VERSION 5.7 ;
BUSBITCHARS "[]" ;
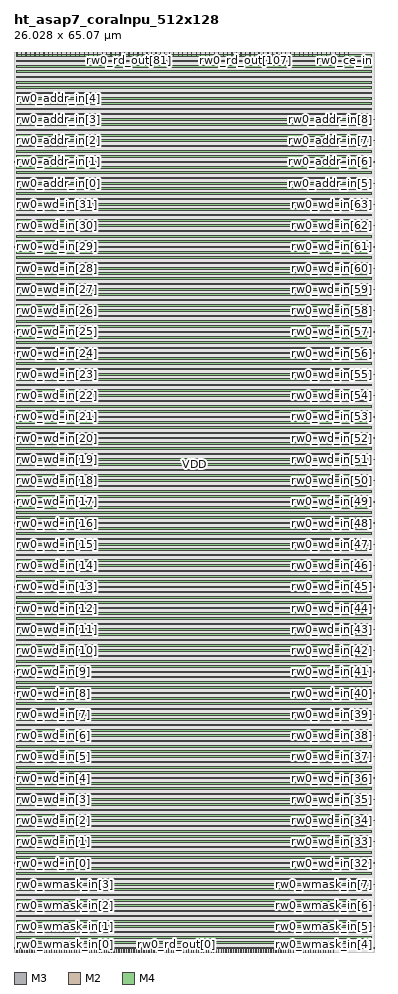
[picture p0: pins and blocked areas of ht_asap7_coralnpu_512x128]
MACRO ht_asap7_coralnpu_512x128
  FOREIGN ht_asap7_coralnpu_512x128 0 0 ;
  SYMMETRY X Y R90 ;
  SIZE 26.028 BY 65.070 ;
  CLASS BLOCK ;
  PIN rw0_wmask_in[0]
    DIRECTION INPUT ;
    USE SIGNAL ;
    SHAPE ABUTMENT ;
    PORT
      LAYER M3 ;
      RECT 0.000 0.276 0.072 0.300 ;
    END
  END rw0_wmask_in[0]
  PIN rw0_wmask_in[1]
    DIRECTION INPUT ;
    USE SIGNAL ;
    SHAPE ABUTMENT ;
    PORT
      LAYER M3 ;
      RECT 0.000 1.812 0.072 1.836 ;
    END
  END rw0_wmask_in[1]
  PIN rw0_wmask_in[2]
    DIRECTION INPUT ;
    USE SIGNAL ;
    SHAPE ABUTMENT ;
    PORT
      LAYER M3 ;
      RECT 0.000 3.348 0.072 3.372 ;
    END
  END rw0_wmask_in[2]
  PIN rw0_wmask_in[3]
    DIRECTION INPUT ;
    USE SIGNAL ;
    SHAPE ABUTMENT ;
    PORT
      LAYER M3 ;
      RECT 0.000 4.884 0.072 4.908 ;
    END
  END rw0_wmask_in[3]
  PIN rw0_wmask_in[4]
    DIRECTION INPUT ;
    USE SIGNAL ;
    SHAPE ABUTMENT ;
    PORT
      LAYER M3 ;
      RECT 25.956 0.276 26.028 0.300 ;
    END
  END rw0_wmask_in[4]
  PIN rw0_wmask_in[5]
    DIRECTION INPUT ;
    USE SIGNAL ;
    SHAPE ABUTMENT ;
    PORT
      LAYER M3 ;
      RECT 25.956 1.812 26.028 1.836 ;
    END
  END rw0_wmask_in[5]
  PIN rw0_wmask_in[6]
    DIRECTION INPUT ;
    USE SIGNAL ;
    SHAPE ABUTMENT ;
    PORT
      LAYER M3 ;
      RECT 25.956 3.348 26.028 3.372 ;
    END
  END rw0_wmask_in[6]
  PIN rw0_wmask_in[7]
    DIRECTION INPUT ;
    USE SIGNAL ;
    SHAPE ABUTMENT ;
    PORT
      LAYER M3 ;
      RECT 25.956 4.884 26.028 4.908 ;
    END
  END rw0_wmask_in[7]
  PIN rw0_wmask_in[8]
    DIRECTION INPUT ;
    USE SIGNAL ;
    SHAPE ABUTMENT ;
    PORT
      LAYER M2 ;
      RECT 0.207 64.800 0.225 65.070 ;
    END
  END rw0_wmask_in[8]
  PIN rw0_wmask_in[9]
    DIRECTION INPUT ;
    USE SIGNAL ;
    SHAPE ABUTMENT ;
    PORT
      LAYER M2 ;
      RECT 0.531 64.800 0.549 65.070 ;
    END
  END rw0_wmask_in[9]
  PIN rw0_wmask_in[10]
    DIRECTION INPUT ;
    USE SIGNAL ;
    SHAPE ABUTMENT ;
    PORT
      LAYER M2 ;
      RECT 0.855 64.800 0.873 65.070 ;
    END
  END rw0_wmask_in[10]
  PIN rw0_wmask_in[11]
    DIRECTION INPUT ;
    USE SIGNAL ;
    SHAPE ABUTMENT ;
    PORT
      LAYER M2 ;
      RECT 1.179 64.800 1.197 65.070 ;
    END
  END rw0_wmask_in[11]
  PIN rw0_wmask_in[12]
    DIRECTION INPUT ;
    USE SIGNAL ;
    SHAPE ABUTMENT ;
    PORT
      LAYER M2 ;
      RECT 1.503 64.800 1.521 65.070 ;
    END
  END rw0_wmask_in[12]
  PIN rw0_wmask_in[13]
    DIRECTION INPUT ;
    USE SIGNAL ;
    SHAPE ABUTMENT ;
    PORT
      LAYER M2 ;
      RECT 1.827 64.800 1.845 65.070 ;
    END
  END rw0_wmask_in[13]
  PIN rw0_wmask_in[14]
    DIRECTION INPUT ;
    USE SIGNAL ;
    SHAPE ABUTMENT ;
    PORT
      LAYER M2 ;
      RECT 2.151 64.800 2.169 65.070 ;
    END
  END rw0_wmask_in[14]
  PIN rw0_wmask_in[15]
    DIRECTION INPUT ;
    USE SIGNAL ;
    SHAPE ABUTMENT ;
    PORT
      LAYER M2 ;
      RECT 2.475 64.800 2.493 65.070 ;
    END
  END rw0_wmask_in[15]
  PIN rw0_wd_in[0]
    DIRECTION INPUT ;
    USE SIGNAL ;
    SHAPE ABUTMENT ;
    PORT
      LAYER M3 ;
      RECT 0.000 6.420 0.072 6.444 ;
    END
  END rw0_wd_in[0]
  PIN rw0_wd_in[1]
    DIRECTION INPUT ;
    USE SIGNAL ;
    SHAPE ABUTMENT ;
    PORT
      LAYER M3 ;
      RECT 0.000 7.956 0.072 7.980 ;
    END
  END rw0_wd_in[1]
  PIN rw0_wd_in[2]
    DIRECTION INPUT ;
    USE SIGNAL ;
    SHAPE ABUTMENT ;
    PORT
      LAYER M3 ;
      RECT 0.000 9.492 0.072 9.516 ;
    END
  END rw0_wd_in[2]
  PIN rw0_wd_in[3]
    DIRECTION INPUT ;
    USE SIGNAL ;
    SHAPE ABUTMENT ;
    PORT
      LAYER M3 ;
      RECT 0.000 11.028 0.072 11.052 ;
    END
  END rw0_wd_in[3]
  PIN rw0_wd_in[4]
    DIRECTION INPUT ;
    USE SIGNAL ;
    SHAPE ABUTMENT ;
    PORT
      LAYER M3 ;
      RECT 0.000 12.564 0.072 12.588 ;
    END
  END rw0_wd_in[4]
  PIN rw0_wd_in[5]
    DIRECTION INPUT ;
    USE SIGNAL ;
    SHAPE ABUTMENT ;
    PORT
      LAYER M3 ;
      RECT 0.000 14.100 0.072 14.124 ;
    END
  END rw0_wd_in[5]
  PIN rw0_wd_in[6]
    DIRECTION INPUT ;
    USE SIGNAL ;
    SHAPE ABUTMENT ;
    PORT
      LAYER M3 ;
      RECT 0.000 15.636 0.072 15.660 ;
    END
  END rw0_wd_in[6]
  PIN rw0_wd_in[7]
    DIRECTION INPUT ;
    USE SIGNAL ;
    SHAPE ABUTMENT ;
    PORT
      LAYER M3 ;
      RECT 0.000 17.172 0.072 17.196 ;
    END
  END rw0_wd_in[7]
  PIN rw0_wd_in[8]
    DIRECTION INPUT ;
    USE SIGNAL ;
    SHAPE ABUTMENT ;
    PORT
      LAYER M3 ;
      RECT 0.000 18.708 0.072 18.732 ;
    END
  END rw0_wd_in[8]
  PIN rw0_wd_in[9]
    DIRECTION INPUT ;
    USE SIGNAL ;
    SHAPE ABUTMENT ;
    PORT
      LAYER M3 ;
      RECT 0.000 20.244 0.072 20.268 ;
    END
  END rw0_wd_in[9]
  PIN rw0_wd_in[10]
    DIRECTION INPUT ;
    USE SIGNAL ;
    SHAPE ABUTMENT ;
    PORT
      LAYER M3 ;
      RECT 0.000 21.780 0.072 21.804 ;
    END
  END rw0_wd_in[10]
  PIN rw0_wd_in[11]
    DIRECTION INPUT ;
    USE SIGNAL ;
    SHAPE ABUTMENT ;
    PORT
      LAYER M3 ;
      RECT 0.000 23.316 0.072 23.340 ;
    END
  END rw0_wd_in[11]
  PIN rw0_wd_in[12]
    DIRECTION INPUT ;
    USE SIGNAL ;
    SHAPE ABUTMENT ;
    PORT
      LAYER M3 ;
      RECT 0.000 24.852 0.072 24.876 ;
    END
  END rw0_wd_in[12]
  PIN rw0_wd_in[13]
    DIRECTION INPUT ;
    USE SIGNAL ;
    SHAPE ABUTMENT ;
    PORT
      LAYER M3 ;
      RECT 0.000 26.388 0.072 26.412 ;
    END
  END rw0_wd_in[13]
  PIN rw0_wd_in[14]
    DIRECTION INPUT ;
    USE SIGNAL ;
    SHAPE ABUTMENT ;
    PORT
      LAYER M3 ;
      RECT 0.000 27.924 0.072 27.948 ;
    END
  END rw0_wd_in[14]
  PIN rw0_wd_in[15]
    DIRECTION INPUT ;
    USE SIGNAL ;
    SHAPE ABUTMENT ;
    PORT
      LAYER M3 ;
      RECT 0.000 29.460 0.072 29.484 ;
    END
  END rw0_wd_in[15]
  PIN rw0_wd_in[16]
    DIRECTION INPUT ;
    USE SIGNAL ;
    SHAPE ABUTMENT ;
    PORT
      LAYER M3 ;
      RECT 0.000 30.996 0.072 31.020 ;
    END
  END rw0_wd_in[16]
  PIN rw0_wd_in[17]
    DIRECTION INPUT ;
    USE SIGNAL ;
    SHAPE ABUTMENT ;
    PORT
      LAYER M3 ;
      RECT 0.000 32.532 0.072 32.556 ;
    END
  END rw0_wd_in[17]
  PIN rw0_wd_in[18]
    DIRECTION INPUT ;
    USE SIGNAL ;
    SHAPE ABUTMENT ;
    PORT
      LAYER M3 ;
      RECT 0.000 34.068 0.072 34.092 ;
    END
  END rw0_wd_in[18]
  PIN rw0_wd_in[19]
    DIRECTION INPUT ;
    USE SIGNAL ;
    SHAPE ABUTMENT ;
    PORT
      LAYER M3 ;
      RECT 0.000 35.604 0.072 35.628 ;
    END
  END rw0_wd_in[19]
  PIN rw0_wd_in[20]
    DIRECTION INPUT ;
    USE SIGNAL ;
    SHAPE ABUTMENT ;
    PORT
      LAYER M3 ;
      RECT 0.000 37.140 0.072 37.164 ;
    END
  END rw0_wd_in[20]
  PIN rw0_wd_in[21]
    DIRECTION INPUT ;
    USE SIGNAL ;
    SHAPE ABUTMENT ;
    PORT
      LAYER M3 ;
      RECT 0.000 38.676 0.072 38.700 ;
    END
  END rw0_wd_in[21]
  PIN rw0_wd_in[22]
    DIRECTION INPUT ;
    USE SIGNAL ;
    SHAPE ABUTMENT ;
    PORT
      LAYER M3 ;
      RECT 0.000 40.212 0.072 40.236 ;
    END
  END rw0_wd_in[22]
  PIN rw0_wd_in[23]
    DIRECTION INPUT ;
    USE SIGNAL ;
    SHAPE ABUTMENT ;
    PORT
      LAYER M3 ;
      RECT 0.000 41.748 0.072 41.772 ;
    END
  END rw0_wd_in[23]
  PIN rw0_wd_in[24]
    DIRECTION INPUT ;
    USE SIGNAL ;
    SHAPE ABUTMENT ;
    PORT
      LAYER M3 ;
      RECT 0.000 43.284 0.072 43.308 ;
    END
  END rw0_wd_in[24]
  PIN rw0_wd_in[25]
    DIRECTION INPUT ;
    USE SIGNAL ;
    SHAPE ABUTMENT ;
    PORT
      LAYER M3 ;
      RECT 0.000 44.820 0.072 44.844 ;
    END
  END rw0_wd_in[25]
  PIN rw0_wd_in[26]
    DIRECTION INPUT ;
    USE SIGNAL ;
    SHAPE ABUTMENT ;
    PORT
      LAYER M3 ;
      RECT 0.000 46.356 0.072 46.380 ;
    END
  END rw0_wd_in[26]
  PIN rw0_wd_in[27]
    DIRECTION INPUT ;
    USE SIGNAL ;
    SHAPE ABUTMENT ;
    PORT
      LAYER M3 ;
      RECT 0.000 47.892 0.072 47.916 ;
    END
  END rw0_wd_in[27]
  PIN rw0_wd_in[28]
    DIRECTION INPUT ;
    USE SIGNAL ;
    SHAPE ABUTMENT ;
    PORT
      LAYER M3 ;
      RECT 0.000 49.428 0.072 49.452 ;
    END
  END rw0_wd_in[28]
  PIN rw0_wd_in[29]
    DIRECTION INPUT ;
    USE SIGNAL ;
    SHAPE ABUTMENT ;
    PORT
      LAYER M3 ;
      RECT 0.000 50.964 0.072 50.988 ;
    END
  END rw0_wd_in[29]
  PIN rw0_wd_in[30]
    DIRECTION INPUT ;
    USE SIGNAL ;
    SHAPE ABUTMENT ;
    PORT
      LAYER M3 ;
      RECT 0.000 52.500 0.072 52.524 ;
    END
  END rw0_wd_in[30]
  PIN rw0_wd_in[31]
    DIRECTION INPUT ;
    USE SIGNAL ;
    SHAPE ABUTMENT ;
    PORT
      LAYER M3 ;
      RECT 0.000 54.036 0.072 54.060 ;
    END
  END rw0_wd_in[31]
  PIN rw0_wd_in[32]
    DIRECTION INPUT ;
    USE SIGNAL ;
    SHAPE ABUTMENT ;
    PORT
      LAYER M3 ;
      RECT 25.956 6.420 26.028 6.444 ;
    END
  END rw0_wd_in[32]
  PIN rw0_wd_in[33]
    DIRECTION INPUT ;
    USE SIGNAL ;
    SHAPE ABUTMENT ;
    PORT
      LAYER M3 ;
      RECT 25.956 7.956 26.028 7.980 ;
    END
  END rw0_wd_in[33]
  PIN rw0_wd_in[34]
    DIRECTION INPUT ;
    USE SIGNAL ;
    SHAPE ABUTMENT ;
    PORT
      LAYER M3 ;
      RECT 25.956 9.492 26.028 9.516 ;
    END
  END rw0_wd_in[34]
  PIN rw0_wd_in[35]
    DIRECTION INPUT ;
    USE SIGNAL ;
    SHAPE ABUTMENT ;
    PORT
      LAYER M3 ;
      RECT 25.956 11.028 26.028 11.052 ;
    END
  END rw0_wd_in[35]
  PIN rw0_wd_in[36]
    DIRECTION INPUT ;
    USE SIGNAL ;
    SHAPE ABUTMENT ;
    PORT
      LAYER M3 ;
      RECT 25.956 12.564 26.028 12.588 ;
    END
  END rw0_wd_in[36]
  PIN rw0_wd_in[37]
    DIRECTION INPUT ;
    USE SIGNAL ;
    SHAPE ABUTMENT ;
    PORT
      LAYER M3 ;
      RECT 25.956 14.100 26.028 14.124 ;
    END
  END rw0_wd_in[37]
  PIN rw0_wd_in[38]
    DIRECTION INPUT ;
    USE SIGNAL ;
    SHAPE ABUTMENT ;
    PORT
      LAYER M3 ;
      RECT 25.956 15.636 26.028 15.660 ;
    END
  END rw0_wd_in[38]
  PIN rw0_wd_in[39]
    DIRECTION INPUT ;
    USE SIGNAL ;
    SHAPE ABUTMENT ;
    PORT
      LAYER M3 ;
      RECT 25.956 17.172 26.028 17.196 ;
    END
  END rw0_wd_in[39]
  PIN rw0_wd_in[40]
    DIRECTION INPUT ;
    USE SIGNAL ;
    SHAPE ABUTMENT ;
    PORT
      LAYER M3 ;
      RECT 25.956 18.708 26.028 18.732 ;
    END
  END rw0_wd_in[40]
  PIN rw0_wd_in[41]
    DIRECTION INPUT ;
    USE SIGNAL ;
    SHAPE ABUTMENT ;
    PORT
      LAYER M3 ;
      RECT 25.956 20.244 26.028 20.268 ;
    END
  END rw0_wd_in[41]
  PIN rw0_wd_in[42]
    DIRECTION INPUT ;
    USE SIGNAL ;
    SHAPE ABUTMENT ;
    PORT
      LAYER M3 ;
      RECT 25.956 21.780 26.028 21.804 ;
    END
  END rw0_wd_in[42]
  PIN rw0_wd_in[43]
    DIRECTION INPUT ;
    USE SIGNAL ;
    SHAPE ABUTMENT ;
    PORT
      LAYER M3 ;
      RECT 25.956 23.316 26.028 23.340 ;
    END
  END rw0_wd_in[43]
  PIN rw0_wd_in[44]
    DIRECTION INPUT ;
    USE SIGNAL ;
    SHAPE ABUTMENT ;
    PORT
      LAYER M3 ;
      RECT 25.956 24.852 26.028 24.876 ;
    END
  END rw0_wd_in[44]
  PIN rw0_wd_in[45]
    DIRECTION INPUT ;
    USE SIGNAL ;
    SHAPE ABUTMENT ;
    PORT
      LAYER M3 ;
      RECT 25.956 26.388 26.028 26.412 ;
    END
  END rw0_wd_in[45]
  PIN rw0_wd_in[46]
    DIRECTION INPUT ;
    USE SIGNAL ;
    SHAPE ABUTMENT ;
    PORT
      LAYER M3 ;
      RECT 25.956 27.924 26.028 27.948 ;
    END
  END rw0_wd_in[46]
  PIN rw0_wd_in[47]
    DIRECTION INPUT ;
    USE SIGNAL ;
    SHAPE ABUTMENT ;
    PORT
      LAYER M3 ;
      RECT 25.956 29.460 26.028 29.484 ;
    END
  END rw0_wd_in[47]
  PIN rw0_wd_in[48]
    DIRECTION INPUT ;
    USE SIGNAL ;
    SHAPE ABUTMENT ;
    PORT
      LAYER M3 ;
      RECT 25.956 30.996 26.028 31.020 ;
    END
  END rw0_wd_in[48]
  PIN rw0_wd_in[49]
    DIRECTION INPUT ;
    USE SIGNAL ;
    SHAPE ABUTMENT ;
    PORT
      LAYER M3 ;
      RECT 25.956 32.532 26.028 32.556 ;
    END
  END rw0_wd_in[49]
  PIN rw0_wd_in[50]
    DIRECTION INPUT ;
    USE SIGNAL ;
    SHAPE ABUTMENT ;
    PORT
      LAYER M3 ;
      RECT 25.956 34.068 26.028 34.092 ;
    END
  END rw0_wd_in[50]
  PIN rw0_wd_in[51]
    DIRECTION INPUT ;
    USE SIGNAL ;
    SHAPE ABUTMENT ;
    PORT
      LAYER M3 ;
      RECT 25.956 35.604 26.028 35.628 ;
    END
  END rw0_wd_in[51]
  PIN rw0_wd_in[52]
    DIRECTION INPUT ;
    USE SIGNAL ;
    SHAPE ABUTMENT ;
    PORT
      LAYER M3 ;
      RECT 25.956 37.140 26.028 37.164 ;
    END
  END rw0_wd_in[52]
  PIN rw0_wd_in[53]
    DIRECTION INPUT ;
    USE SIGNAL ;
    SHAPE ABUTMENT ;
    PORT
      LAYER M3 ;
      RECT 25.956 38.676 26.028 38.700 ;
    END
  END rw0_wd_in[53]
  PIN rw0_wd_in[54]
    DIRECTION INPUT ;
    USE SIGNAL ;
    SHAPE ABUTMENT ;
    PORT
      LAYER M3 ;
      RECT 25.956 40.212 26.028 40.236 ;
    END
  END rw0_wd_in[54]
  PIN rw0_wd_in[55]
    DIRECTION INPUT ;
    USE SIGNAL ;
    SHAPE ABUTMENT ;
    PORT
      LAYER M3 ;
      RECT 25.956 41.748 26.028 41.772 ;
    END
  END rw0_wd_in[55]
  PIN rw0_wd_in[56]
    DIRECTION INPUT ;
    USE SIGNAL ;
    SHAPE ABUTMENT ;
    PORT
      LAYER M3 ;
      RECT 25.956 43.284 26.028 43.308 ;
    END
  END rw0_wd_in[56]
  PIN rw0_wd_in[57]
    DIRECTION INPUT ;
    USE SIGNAL ;
    SHAPE ABUTMENT ;
    PORT
      LAYER M3 ;
      RECT 25.956 44.820 26.028 44.844 ;
    END
  END rw0_wd_in[57]
  PIN rw0_wd_in[58]
    DIRECTION INPUT ;
    USE SIGNAL ;
    SHAPE ABUTMENT ;
    PORT
      LAYER M3 ;
      RECT 25.956 46.356 26.028 46.380 ;
    END
  END rw0_wd_in[58]
  PIN rw0_wd_in[59]
    DIRECTION INPUT ;
    USE SIGNAL ;
    SHAPE ABUTMENT ;
    PORT
      LAYER M3 ;
      RECT 25.956 47.892 26.028 47.916 ;
    END
  END rw0_wd_in[59]
  PIN rw0_wd_in[60]
    DIRECTION INPUT ;
    USE SIGNAL ;
    SHAPE ABUTMENT ;
    PORT
      LAYER M3 ;
      RECT 25.956 49.428 26.028 49.452 ;
    END
  END rw0_wd_in[60]
  PIN rw0_wd_in[61]
    DIRECTION INPUT ;
    USE SIGNAL ;
    SHAPE ABUTMENT ;
    PORT
      LAYER M3 ;
      RECT 25.956 50.964 26.028 50.988 ;
    END
  END rw0_wd_in[61]
  PIN rw0_wd_in[62]
    DIRECTION INPUT ;
    USE SIGNAL ;
    SHAPE ABUTMENT ;
    PORT
      LAYER M3 ;
      RECT 25.956 52.500 26.028 52.524 ;
    END
  END rw0_wd_in[62]
  PIN rw0_wd_in[63]
    DIRECTION INPUT ;
    USE SIGNAL ;
    SHAPE ABUTMENT ;
    PORT
      LAYER M3 ;
      RECT 25.956 54.036 26.028 54.060 ;
    END
  END rw0_wd_in[63]
  PIN rw0_wd_in[64]
    DIRECTION INPUT ;
    USE SIGNAL ;
    SHAPE ABUTMENT ;
    PORT
      LAYER M2 ;
      RECT 0.207 0.000 0.225 0.270 ;
    END
  END rw0_wd_in[64]
  PIN rw0_wd_in[65]
    DIRECTION INPUT ;
    USE SIGNAL ;
    SHAPE ABUTMENT ;
    PORT
      LAYER M2 ;
      RECT 0.387 0.000 0.405 0.270 ;
    END
  END rw0_wd_in[65]
  PIN rw0_wd_in[66]
    DIRECTION INPUT ;
    USE SIGNAL ;
    SHAPE ABUTMENT ;
    PORT
      LAYER M2 ;
      RECT 0.567 0.000 0.585 0.270 ;
    END
  END rw0_wd_in[66]
  PIN rw0_wd_in[67]
    DIRECTION INPUT ;
    USE SIGNAL ;
    SHAPE ABUTMENT ;
    PORT
      LAYER M2 ;
      RECT 0.747 0.000 0.765 0.270 ;
    END
  END rw0_wd_in[67]
  PIN rw0_wd_in[68]
    DIRECTION INPUT ;
    USE SIGNAL ;
    SHAPE ABUTMENT ;
    PORT
      LAYER M2 ;
      RECT 0.927 0.000 0.945 0.270 ;
    END
  END rw0_wd_in[68]
  PIN rw0_wd_in[69]
    DIRECTION INPUT ;
    USE SIGNAL ;
    SHAPE ABUTMENT ;
    PORT
      LAYER M2 ;
      RECT 1.107 0.000 1.125 0.270 ;
    END
  END rw0_wd_in[69]
  PIN rw0_wd_in[70]
    DIRECTION INPUT ;
    USE SIGNAL ;
    SHAPE ABUTMENT ;
    PORT
      LAYER M2 ;
      RECT 1.287 0.000 1.305 0.270 ;
    END
  END rw0_wd_in[70]
  PIN rw0_wd_in[71]
    DIRECTION INPUT ;
    USE SIGNAL ;
    SHAPE ABUTMENT ;
    PORT
      LAYER M2 ;
      RECT 1.467 0.000 1.485 0.270 ;
    END
  END rw0_wd_in[71]
  PIN rw0_wd_in[72]
    DIRECTION INPUT ;
    USE SIGNAL ;
    SHAPE ABUTMENT ;
    PORT
      LAYER M2 ;
      RECT 1.647 0.000 1.665 0.270 ;
    END
  END rw0_wd_in[72]
  PIN rw0_wd_in[73]
    DIRECTION INPUT ;
    USE SIGNAL ;
    SHAPE ABUTMENT ;
    PORT
      LAYER M2 ;
      RECT 1.827 0.000 1.845 0.270 ;
    END
  END rw0_wd_in[73]
  PIN rw0_wd_in[74]
    DIRECTION INPUT ;
    USE SIGNAL ;
    SHAPE ABUTMENT ;
    PORT
      LAYER M2 ;
      RECT 2.007 0.000 2.025 0.270 ;
    END
  END rw0_wd_in[74]
  PIN rw0_wd_in[75]
    DIRECTION INPUT ;
    USE SIGNAL ;
    SHAPE ABUTMENT ;
    PORT
      LAYER M2 ;
      RECT 2.187 0.000 2.205 0.270 ;
    END
  END rw0_wd_in[75]
  PIN rw0_wd_in[76]
    DIRECTION INPUT ;
    USE SIGNAL ;
    SHAPE ABUTMENT ;
    PORT
      LAYER M2 ;
      RECT 2.367 0.000 2.385 0.270 ;
    END
  END rw0_wd_in[76]
  PIN rw0_wd_in[77]
    DIRECTION INPUT ;
    USE SIGNAL ;
    SHAPE ABUTMENT ;
    PORT
      LAYER M2 ;
      RECT 2.547 0.000 2.565 0.270 ;
    END
  END rw0_wd_in[77]
  PIN rw0_wd_in[78]
    DIRECTION INPUT ;
    USE SIGNAL ;
    SHAPE ABUTMENT ;
    PORT
      LAYER M2 ;
      RECT 2.727 0.000 2.745 0.270 ;
    END
  END rw0_wd_in[78]
  PIN rw0_wd_in[79]
    DIRECTION INPUT ;
    USE SIGNAL ;
    SHAPE ABUTMENT ;
    PORT
      LAYER M2 ;
      RECT 2.907 0.000 2.925 0.270 ;
    END
  END rw0_wd_in[79]
  PIN rw0_wd_in[80]
    DIRECTION INPUT ;
    USE SIGNAL ;
    SHAPE ABUTMENT ;
    PORT
      LAYER M2 ;
      RECT 3.087 0.000 3.105 0.270 ;
    END
  END rw0_wd_in[80]
  PIN rw0_wd_in[81]
    DIRECTION INPUT ;
    USE SIGNAL ;
    SHAPE ABUTMENT ;
    PORT
      LAYER M2 ;
      RECT 3.267 0.000 3.285 0.270 ;
    END
  END rw0_wd_in[81]
  PIN rw0_wd_in[82]
    DIRECTION INPUT ;
    USE SIGNAL ;
    SHAPE ABUTMENT ;
    PORT
      LAYER M2 ;
      RECT 3.447 0.000 3.465 0.270 ;
    END
  END rw0_wd_in[82]
  PIN rw0_wd_in[83]
    DIRECTION INPUT ;
    USE SIGNAL ;
    SHAPE ABUTMENT ;
    PORT
      LAYER M2 ;
      RECT 3.627 0.000 3.645 0.270 ;
    END
  END rw0_wd_in[83]
  PIN rw0_wd_in[84]
    DIRECTION INPUT ;
    USE SIGNAL ;
    SHAPE ABUTMENT ;
    PORT
      LAYER M2 ;
      RECT 3.807 0.000 3.825 0.270 ;
    END
  END rw0_wd_in[84]
  PIN rw0_wd_in[85]
    DIRECTION INPUT ;
    USE SIGNAL ;
    SHAPE ABUTMENT ;
    PORT
      LAYER M2 ;
      RECT 3.987 0.000 4.005 0.270 ;
    END
  END rw0_wd_in[85]
  PIN rw0_wd_in[86]
    DIRECTION INPUT ;
    USE SIGNAL ;
    SHAPE ABUTMENT ;
    PORT
      LAYER M2 ;
      RECT 4.167 0.000 4.185 0.270 ;
    END
  END rw0_wd_in[86]
  PIN rw0_wd_in[87]
    DIRECTION INPUT ;
    USE SIGNAL ;
    SHAPE ABUTMENT ;
    PORT
      LAYER M2 ;
      RECT 4.347 0.000 4.365 0.270 ;
    END
  END rw0_wd_in[87]
  PIN rw0_wd_in[88]
    DIRECTION INPUT ;
    USE SIGNAL ;
    SHAPE ABUTMENT ;
    PORT
      LAYER M2 ;
      RECT 4.527 0.000 4.545 0.270 ;
    END
  END rw0_wd_in[88]
  PIN rw0_wd_in[89]
    DIRECTION INPUT ;
    USE SIGNAL ;
    SHAPE ABUTMENT ;
    PORT
      LAYER M2 ;
      RECT 4.707 0.000 4.725 0.270 ;
    END
  END rw0_wd_in[89]
  PIN rw0_wd_in[90]
    DIRECTION INPUT ;
    USE SIGNAL ;
    SHAPE ABUTMENT ;
    PORT
      LAYER M2 ;
      RECT 4.887 0.000 4.905 0.270 ;
    END
  END rw0_wd_in[90]
  PIN rw0_wd_in[91]
    DIRECTION INPUT ;
    USE SIGNAL ;
    SHAPE ABUTMENT ;
    PORT
      LAYER M2 ;
      RECT 5.067 0.000 5.085 0.270 ;
    END
  END rw0_wd_in[91]
  PIN rw0_wd_in[92]
    DIRECTION INPUT ;
    USE SIGNAL ;
    SHAPE ABUTMENT ;
    PORT
      LAYER M2 ;
      RECT 5.247 0.000 5.265 0.270 ;
    END
  END rw0_wd_in[92]
  PIN rw0_wd_in[93]
    DIRECTION INPUT ;
    USE SIGNAL ;
    SHAPE ABUTMENT ;
    PORT
      LAYER M2 ;
      RECT 5.427 0.000 5.445 0.270 ;
    END
  END rw0_wd_in[93]
  PIN rw0_wd_in[94]
    DIRECTION INPUT ;
    USE SIGNAL ;
    SHAPE ABUTMENT ;
    PORT
      LAYER M2 ;
      RECT 5.607 0.000 5.625 0.270 ;
    END
  END rw0_wd_in[94]
  PIN rw0_wd_in[95]
    DIRECTION INPUT ;
    USE SIGNAL ;
    SHAPE ABUTMENT ;
    PORT
      LAYER M2 ;
      RECT 5.787 0.000 5.805 0.270 ;
    END
  END rw0_wd_in[95]
  PIN rw0_wd_in[96]
    DIRECTION INPUT ;
    USE SIGNAL ;
    SHAPE ABUTMENT ;
    PORT
      LAYER M2 ;
      RECT 5.967 0.000 5.985 0.270 ;
    END
  END rw0_wd_in[96]
  PIN rw0_wd_in[97]
    DIRECTION INPUT ;
    USE SIGNAL ;
    SHAPE ABUTMENT ;
    PORT
      LAYER M2 ;
      RECT 6.147 0.000 6.165 0.270 ;
    END
  END rw0_wd_in[97]
  PIN rw0_wd_in[98]
    DIRECTION INPUT ;
    USE SIGNAL ;
    SHAPE ABUTMENT ;
    PORT
      LAYER M2 ;
      RECT 6.327 0.000 6.345 0.270 ;
    END
  END rw0_wd_in[98]
  PIN rw0_wd_in[99]
    DIRECTION INPUT ;
    USE SIGNAL ;
    SHAPE ABUTMENT ;
    PORT
      LAYER M2 ;
      RECT 6.507 0.000 6.525 0.270 ;
    END
  END rw0_wd_in[99]
  PIN rw0_wd_in[100]
    DIRECTION INPUT ;
    USE SIGNAL ;
    SHAPE ABUTMENT ;
    PORT
      LAYER M2 ;
      RECT 6.687 0.000 6.705 0.270 ;
    END
  END rw0_wd_in[100]
  PIN rw0_wd_in[101]
    DIRECTION INPUT ;
    USE SIGNAL ;
    SHAPE ABUTMENT ;
    PORT
      LAYER M2 ;
      RECT 6.867 0.000 6.885 0.270 ;
    END
  END rw0_wd_in[101]
  PIN rw0_wd_in[102]
    DIRECTION INPUT ;
    USE SIGNAL ;
    SHAPE ABUTMENT ;
    PORT
      LAYER M2 ;
      RECT 7.047 0.000 7.065 0.270 ;
    END
  END rw0_wd_in[102]
  PIN rw0_wd_in[103]
    DIRECTION INPUT ;
    USE SIGNAL ;
    SHAPE ABUTMENT ;
    PORT
      LAYER M2 ;
      RECT 7.227 0.000 7.245 0.270 ;
    END
  END rw0_wd_in[103]
  PIN rw0_wd_in[104]
    DIRECTION INPUT ;
    USE SIGNAL ;
    SHAPE ABUTMENT ;
    PORT
      LAYER M2 ;
      RECT 7.407 0.000 7.425 0.270 ;
    END
  END rw0_wd_in[104]
  PIN rw0_wd_in[105]
    DIRECTION INPUT ;
    USE SIGNAL ;
    SHAPE ABUTMENT ;
    PORT
      LAYER M2 ;
      RECT 7.587 0.000 7.605 0.270 ;
    END
  END rw0_wd_in[105]
  PIN rw0_wd_in[106]
    DIRECTION INPUT ;
    USE SIGNAL ;
    SHAPE ABUTMENT ;
    PORT
      LAYER M2 ;
      RECT 7.767 0.000 7.785 0.270 ;
    END
  END rw0_wd_in[106]
  PIN rw0_wd_in[107]
    DIRECTION INPUT ;
    USE SIGNAL ;
    SHAPE ABUTMENT ;
    PORT
      LAYER M2 ;
      RECT 7.947 0.000 7.965 0.270 ;
    END
  END rw0_wd_in[107]
  PIN rw0_wd_in[108]
    DIRECTION INPUT ;
    USE SIGNAL ;
    SHAPE ABUTMENT ;
    PORT
      LAYER M2 ;
      RECT 8.127 0.000 8.145 0.270 ;
    END
  END rw0_wd_in[108]
  PIN rw0_wd_in[109]
    DIRECTION INPUT ;
    USE SIGNAL ;
    SHAPE ABUTMENT ;
    PORT
      LAYER M2 ;
      RECT 8.307 0.000 8.325 0.270 ;
    END
  END rw0_wd_in[109]
  PIN rw0_wd_in[110]
    DIRECTION INPUT ;
    USE SIGNAL ;
    SHAPE ABUTMENT ;
    PORT
      LAYER M2 ;
      RECT 8.487 0.000 8.505 0.270 ;
    END
  END rw0_wd_in[110]
  PIN rw0_wd_in[111]
    DIRECTION INPUT ;
    USE SIGNAL ;
    SHAPE ABUTMENT ;
    PORT
      LAYER M2 ;
      RECT 8.667 0.000 8.685 0.270 ;
    END
  END rw0_wd_in[111]
  PIN rw0_wd_in[112]
    DIRECTION INPUT ;
    USE SIGNAL ;
    SHAPE ABUTMENT ;
    PORT
      LAYER M2 ;
      RECT 8.847 0.000 8.865 0.270 ;
    END
  END rw0_wd_in[112]
  PIN rw0_wd_in[113]
    DIRECTION INPUT ;
    USE SIGNAL ;
    SHAPE ABUTMENT ;
    PORT
      LAYER M2 ;
      RECT 9.027 0.000 9.045 0.270 ;
    END
  END rw0_wd_in[113]
  PIN rw0_wd_in[114]
    DIRECTION INPUT ;
    USE SIGNAL ;
    SHAPE ABUTMENT ;
    PORT
      LAYER M2 ;
      RECT 9.207 0.000 9.225 0.270 ;
    END
  END rw0_wd_in[114]
  PIN rw0_wd_in[115]
    DIRECTION INPUT ;
    USE SIGNAL ;
    SHAPE ABUTMENT ;
    PORT
      LAYER M2 ;
      RECT 9.387 0.000 9.405 0.270 ;
    END
  END rw0_wd_in[115]
  PIN rw0_wd_in[116]
    DIRECTION INPUT ;
    USE SIGNAL ;
    SHAPE ABUTMENT ;
    PORT
      LAYER M2 ;
      RECT 9.567 0.000 9.585 0.270 ;
    END
  END rw0_wd_in[116]
  PIN rw0_wd_in[117]
    DIRECTION INPUT ;
    USE SIGNAL ;
    SHAPE ABUTMENT ;
    PORT
      LAYER M2 ;
      RECT 9.747 0.000 9.765 0.270 ;
    END
  END rw0_wd_in[117]
  PIN rw0_wd_in[118]
    DIRECTION INPUT ;
    USE SIGNAL ;
    SHAPE ABUTMENT ;
    PORT
      LAYER M2 ;
      RECT 9.927 0.000 9.945 0.270 ;
    END
  END rw0_wd_in[118]
  PIN rw0_wd_in[119]
    DIRECTION INPUT ;
    USE SIGNAL ;
    SHAPE ABUTMENT ;
    PORT
      LAYER M2 ;
      RECT 10.107 0.000 10.125 0.270 ;
    END
  END rw0_wd_in[119]
  PIN rw0_wd_in[120]
    DIRECTION INPUT ;
    USE SIGNAL ;
    SHAPE ABUTMENT ;
    PORT
      LAYER M2 ;
      RECT 10.287 0.000 10.305 0.270 ;
    END
  END rw0_wd_in[120]
  PIN rw0_wd_in[121]
    DIRECTION INPUT ;
    USE SIGNAL ;
    SHAPE ABUTMENT ;
    PORT
      LAYER M2 ;
      RECT 10.467 0.000 10.485 0.270 ;
    END
  END rw0_wd_in[121]
  PIN rw0_wd_in[122]
    DIRECTION INPUT ;
    USE SIGNAL ;
    SHAPE ABUTMENT ;
    PORT
      LAYER M2 ;
      RECT 10.647 0.000 10.665 0.270 ;
    END
  END rw0_wd_in[122]
  PIN rw0_wd_in[123]
    DIRECTION INPUT ;
    USE SIGNAL ;
    SHAPE ABUTMENT ;
    PORT
      LAYER M2 ;
      RECT 10.827 0.000 10.845 0.270 ;
    END
  END rw0_wd_in[123]
  PIN rw0_wd_in[124]
    DIRECTION INPUT ;
    USE SIGNAL ;
    SHAPE ABUTMENT ;
    PORT
      LAYER M2 ;
      RECT 11.007 0.000 11.025 0.270 ;
    END
  END rw0_wd_in[124]
  PIN rw0_wd_in[125]
    DIRECTION INPUT ;
    USE SIGNAL ;
    SHAPE ABUTMENT ;
    PORT
      LAYER M2 ;
      RECT 11.187 0.000 11.205 0.270 ;
    END
  END rw0_wd_in[125]
  PIN rw0_wd_in[126]
    DIRECTION INPUT ;
    USE SIGNAL ;
    SHAPE ABUTMENT ;
    PORT
      LAYER M2 ;
      RECT 11.367 0.000 11.385 0.270 ;
    END
  END rw0_wd_in[126]
  PIN rw0_wd_in[127]
    DIRECTION INPUT ;
    USE SIGNAL ;
    SHAPE ABUTMENT ;
    PORT
      LAYER M2 ;
      RECT 11.547 0.000 11.565 0.270 ;
    END
  END rw0_wd_in[127]
  PIN rw0_rd_out[0]
    DIRECTION OUTPUT ;
    USE SIGNAL ;
    SHAPE ABUTMENT ;
    PORT
      LAYER M2 ;
      RECT 11.727 0.000 11.745 0.270 ;
    END
  END rw0_rd_out[0]
  PIN rw0_rd_out[1]
    DIRECTION OUTPUT ;
    USE SIGNAL ;
    SHAPE ABUTMENT ;
    PORT
      LAYER M2 ;
      RECT 11.907 0.000 11.925 0.270 ;
    END
  END rw0_rd_out[1]
  PIN rw0_rd_out[2]
    DIRECTION OUTPUT ;
    USE SIGNAL ;
    SHAPE ABUTMENT ;
    PORT
      LAYER M2 ;
      RECT 12.087 0.000 12.105 0.270 ;
    END
  END rw0_rd_out[2]
  PIN rw0_rd_out[3]
    DIRECTION OUTPUT ;
    USE SIGNAL ;
    SHAPE ABUTMENT ;
    PORT
      LAYER M2 ;
      RECT 12.267 0.000 12.285 0.270 ;
    END
  END rw0_rd_out[3]
  PIN rw0_rd_out[4]
    DIRECTION OUTPUT ;
    USE SIGNAL ;
    SHAPE ABUTMENT ;
    PORT
      LAYER M2 ;
      RECT 12.447 0.000 12.465 0.270 ;
    END
  END rw0_rd_out[4]
  PIN rw0_rd_out[5]
    DIRECTION OUTPUT ;
    USE SIGNAL ;
    SHAPE ABUTMENT ;
    PORT
      LAYER M2 ;
      RECT 12.627 0.000 12.645 0.270 ;
    END
  END rw0_rd_out[5]
  PIN rw0_rd_out[6]
    DIRECTION OUTPUT ;
    USE SIGNAL ;
    SHAPE ABUTMENT ;
    PORT
      LAYER M2 ;
      RECT 12.807 0.000 12.825 0.270 ;
    END
  END rw0_rd_out[6]
  PIN rw0_rd_out[7]
    DIRECTION OUTPUT ;
    USE SIGNAL ;
    SHAPE ABUTMENT ;
    PORT
      LAYER M2 ;
      RECT 12.987 0.000 13.005 0.270 ;
    END
  END rw0_rd_out[7]
  PIN rw0_rd_out[8]
    DIRECTION OUTPUT ;
    USE SIGNAL ;
    SHAPE ABUTMENT ;
    PORT
      LAYER M2 ;
      RECT 13.167 0.000 13.185 0.270 ;
    END
  END rw0_rd_out[8]
  PIN rw0_rd_out[9]
    DIRECTION OUTPUT ;
    USE SIGNAL ;
    SHAPE ABUTMENT ;
    PORT
      LAYER M2 ;
      RECT 13.347 0.000 13.365 0.270 ;
    END
  END rw0_rd_out[9]
  PIN rw0_rd_out[10]
    DIRECTION OUTPUT ;
    USE SIGNAL ;
    SHAPE ABUTMENT ;
    PORT
      LAYER M2 ;
      RECT 13.527 0.000 13.545 0.270 ;
    END
  END rw0_rd_out[10]
  PIN rw0_rd_out[11]
    DIRECTION OUTPUT ;
    USE SIGNAL ;
    SHAPE ABUTMENT ;
    PORT
      LAYER M2 ;
      RECT 13.707 0.000 13.725 0.270 ;
    END
  END rw0_rd_out[11]
  PIN rw0_rd_out[12]
    DIRECTION OUTPUT ;
    USE SIGNAL ;
    SHAPE ABUTMENT ;
    PORT
      LAYER M2 ;
      RECT 13.887 0.000 13.905 0.270 ;
    END
  END rw0_rd_out[12]
  PIN rw0_rd_out[13]
    DIRECTION OUTPUT ;
    USE SIGNAL ;
    SHAPE ABUTMENT ;
    PORT
      LAYER M2 ;
      RECT 14.067 0.000 14.085 0.270 ;
    END
  END rw0_rd_out[13]
  PIN rw0_rd_out[14]
    DIRECTION OUTPUT ;
    USE SIGNAL ;
    SHAPE ABUTMENT ;
    PORT
      LAYER M2 ;
      RECT 14.247 0.000 14.265 0.270 ;
    END
  END rw0_rd_out[14]
  PIN rw0_rd_out[15]
    DIRECTION OUTPUT ;
    USE SIGNAL ;
    SHAPE ABUTMENT ;
    PORT
      LAYER M2 ;
      RECT 14.427 0.000 14.445 0.270 ;
    END
  END rw0_rd_out[15]
  PIN rw0_rd_out[16]
    DIRECTION OUTPUT ;
    USE SIGNAL ;
    SHAPE ABUTMENT ;
    PORT
      LAYER M2 ;
      RECT 14.607 0.000 14.625 0.270 ;
    END
  END rw0_rd_out[16]
  PIN rw0_rd_out[17]
    DIRECTION OUTPUT ;
    USE SIGNAL ;
    SHAPE ABUTMENT ;
    PORT
      LAYER M2 ;
      RECT 14.787 0.000 14.805 0.270 ;
    END
  END rw0_rd_out[17]
  PIN rw0_rd_out[18]
    DIRECTION OUTPUT ;
    USE SIGNAL ;
    SHAPE ABUTMENT ;
    PORT
      LAYER M2 ;
      RECT 14.967 0.000 14.985 0.270 ;
    END
  END rw0_rd_out[18]
  PIN rw0_rd_out[19]
    DIRECTION OUTPUT ;
    USE SIGNAL ;
    SHAPE ABUTMENT ;
    PORT
      LAYER M2 ;
      RECT 15.147 0.000 15.165 0.270 ;
    END
  END rw0_rd_out[19]
  PIN rw0_rd_out[20]
    DIRECTION OUTPUT ;
    USE SIGNAL ;
    SHAPE ABUTMENT ;
    PORT
      LAYER M2 ;
      RECT 15.327 0.000 15.345 0.270 ;
    END
  END rw0_rd_out[20]
  PIN rw0_rd_out[21]
    DIRECTION OUTPUT ;
    USE SIGNAL ;
    SHAPE ABUTMENT ;
    PORT
      LAYER M2 ;
      RECT 15.507 0.000 15.525 0.270 ;
    END
  END rw0_rd_out[21]
  PIN rw0_rd_out[22]
    DIRECTION OUTPUT ;
    USE SIGNAL ;
    SHAPE ABUTMENT ;
    PORT
      LAYER M2 ;
      RECT 15.687 0.000 15.705 0.270 ;
    END
  END rw0_rd_out[22]
  PIN rw0_rd_out[23]
    DIRECTION OUTPUT ;
    USE SIGNAL ;
    SHAPE ABUTMENT ;
    PORT
      LAYER M2 ;
      RECT 15.867 0.000 15.885 0.270 ;
    END
  END rw0_rd_out[23]
  PIN rw0_rd_out[24]
    DIRECTION OUTPUT ;
    USE SIGNAL ;
    SHAPE ABUTMENT ;
    PORT
      LAYER M2 ;
      RECT 16.047 0.000 16.065 0.270 ;
    END
  END rw0_rd_out[24]
  PIN rw0_rd_out[25]
    DIRECTION OUTPUT ;
    USE SIGNAL ;
    SHAPE ABUTMENT ;
    PORT
      LAYER M2 ;
      RECT 16.227 0.000 16.245 0.270 ;
    END
  END rw0_rd_out[25]
  PIN rw0_rd_out[26]
    DIRECTION OUTPUT ;
    USE SIGNAL ;
    SHAPE ABUTMENT ;
    PORT
      LAYER M2 ;
      RECT 16.407 0.000 16.425 0.270 ;
    END
  END rw0_rd_out[26]
  PIN rw0_rd_out[27]
    DIRECTION OUTPUT ;
    USE SIGNAL ;
    SHAPE ABUTMENT ;
    PORT
      LAYER M2 ;
      RECT 16.587 0.000 16.605 0.270 ;
    END
  END rw0_rd_out[27]
  PIN rw0_rd_out[28]
    DIRECTION OUTPUT ;
    USE SIGNAL ;
    SHAPE ABUTMENT ;
    PORT
      LAYER M2 ;
      RECT 16.767 0.000 16.785 0.270 ;
    END
  END rw0_rd_out[28]
  PIN rw0_rd_out[29]
    DIRECTION OUTPUT ;
    USE SIGNAL ;
    SHAPE ABUTMENT ;
    PORT
      LAYER M2 ;
      RECT 16.947 0.000 16.965 0.270 ;
    END
  END rw0_rd_out[29]
  PIN rw0_rd_out[30]
    DIRECTION OUTPUT ;
    USE SIGNAL ;
    SHAPE ABUTMENT ;
    PORT
      LAYER M2 ;
      RECT 17.127 0.000 17.145 0.270 ;
    END
  END rw0_rd_out[30]
  PIN rw0_rd_out[31]
    DIRECTION OUTPUT ;
    USE SIGNAL ;
    SHAPE ABUTMENT ;
    PORT
      LAYER M2 ;
      RECT 17.307 0.000 17.325 0.270 ;
    END
  END rw0_rd_out[31]
  PIN rw0_rd_out[32]
    DIRECTION OUTPUT ;
    USE SIGNAL ;
    SHAPE ABUTMENT ;
    PORT
      LAYER M2 ;
      RECT 17.487 0.000 17.505 0.270 ;
    END
  END rw0_rd_out[32]
  PIN rw0_rd_out[33]
    DIRECTION OUTPUT ;
    USE SIGNAL ;
    SHAPE ABUTMENT ;
    PORT
      LAYER M2 ;
      RECT 17.667 0.000 17.685 0.270 ;
    END
  END rw0_rd_out[33]
  PIN rw0_rd_out[34]
    DIRECTION OUTPUT ;
    USE SIGNAL ;
    SHAPE ABUTMENT ;
    PORT
      LAYER M2 ;
      RECT 17.847 0.000 17.865 0.270 ;
    END
  END rw0_rd_out[34]
  PIN rw0_rd_out[35]
    DIRECTION OUTPUT ;
    USE SIGNAL ;
    SHAPE ABUTMENT ;
    PORT
      LAYER M2 ;
      RECT 18.027 0.000 18.045 0.270 ;
    END
  END rw0_rd_out[35]
  PIN rw0_rd_out[36]
    DIRECTION OUTPUT ;
    USE SIGNAL ;
    SHAPE ABUTMENT ;
    PORT
      LAYER M2 ;
      RECT 18.207 0.000 18.225 0.270 ;
    END
  END rw0_rd_out[36]
  PIN rw0_rd_out[37]
    DIRECTION OUTPUT ;
    USE SIGNAL ;
    SHAPE ABUTMENT ;
    PORT
      LAYER M2 ;
      RECT 18.387 0.000 18.405 0.270 ;
    END
  END rw0_rd_out[37]
  PIN rw0_rd_out[38]
    DIRECTION OUTPUT ;
    USE SIGNAL ;
    SHAPE ABUTMENT ;
    PORT
      LAYER M2 ;
      RECT 18.567 0.000 18.585 0.270 ;
    END
  END rw0_rd_out[38]
  PIN rw0_rd_out[39]
    DIRECTION OUTPUT ;
    USE SIGNAL ;
    SHAPE ABUTMENT ;
    PORT
      LAYER M2 ;
      RECT 18.747 0.000 18.765 0.270 ;
    END
  END rw0_rd_out[39]
  PIN rw0_rd_out[40]
    DIRECTION OUTPUT ;
    USE SIGNAL ;
    SHAPE ABUTMENT ;
    PORT
      LAYER M2 ;
      RECT 18.927 0.000 18.945 0.270 ;
    END
  END rw0_rd_out[40]
  PIN rw0_rd_out[41]
    DIRECTION OUTPUT ;
    USE SIGNAL ;
    SHAPE ABUTMENT ;
    PORT
      LAYER M2 ;
      RECT 19.107 0.000 19.125 0.270 ;
    END
  END rw0_rd_out[41]
  PIN rw0_rd_out[42]
    DIRECTION OUTPUT ;
    USE SIGNAL ;
    SHAPE ABUTMENT ;
    PORT
      LAYER M2 ;
      RECT 19.287 0.000 19.305 0.270 ;
    END
  END rw0_rd_out[42]
  PIN rw0_rd_out[43]
    DIRECTION OUTPUT ;
    USE SIGNAL ;
    SHAPE ABUTMENT ;
    PORT
      LAYER M2 ;
      RECT 19.467 0.000 19.485 0.270 ;
    END
  END rw0_rd_out[43]
  PIN rw0_rd_out[44]
    DIRECTION OUTPUT ;
    USE SIGNAL ;
    SHAPE ABUTMENT ;
    PORT
      LAYER M2 ;
      RECT 19.647 0.000 19.665 0.270 ;
    END
  END rw0_rd_out[44]
  PIN rw0_rd_out[45]
    DIRECTION OUTPUT ;
    USE SIGNAL ;
    SHAPE ABUTMENT ;
    PORT
      LAYER M2 ;
      RECT 19.827 0.000 19.845 0.270 ;
    END
  END rw0_rd_out[45]
  PIN rw0_rd_out[46]
    DIRECTION OUTPUT ;
    USE SIGNAL ;
    SHAPE ABUTMENT ;
    PORT
      LAYER M2 ;
      RECT 20.007 0.000 20.025 0.270 ;
    END
  END rw0_rd_out[46]
  PIN rw0_rd_out[47]
    DIRECTION OUTPUT ;
    USE SIGNAL ;
    SHAPE ABUTMENT ;
    PORT
      LAYER M2 ;
      RECT 20.187 0.000 20.205 0.270 ;
    END
  END rw0_rd_out[47]
  PIN rw0_rd_out[48]
    DIRECTION OUTPUT ;
    USE SIGNAL ;
    SHAPE ABUTMENT ;
    PORT
      LAYER M2 ;
      RECT 20.367 0.000 20.385 0.270 ;
    END
  END rw0_rd_out[48]
  PIN rw0_rd_out[49]
    DIRECTION OUTPUT ;
    USE SIGNAL ;
    SHAPE ABUTMENT ;
    PORT
      LAYER M2 ;
      RECT 20.547 0.000 20.565 0.270 ;
    END
  END rw0_rd_out[49]
  PIN rw0_rd_out[50]
    DIRECTION OUTPUT ;
    USE SIGNAL ;
    SHAPE ABUTMENT ;
    PORT
      LAYER M2 ;
      RECT 20.727 0.000 20.745 0.270 ;
    END
  END rw0_rd_out[50]
  PIN rw0_rd_out[51]
    DIRECTION OUTPUT ;
    USE SIGNAL ;
    SHAPE ABUTMENT ;
    PORT
      LAYER M2 ;
      RECT 20.907 0.000 20.925 0.270 ;
    END
  END rw0_rd_out[51]
  PIN rw0_rd_out[52]
    DIRECTION OUTPUT ;
    USE SIGNAL ;
    SHAPE ABUTMENT ;
    PORT
      LAYER M2 ;
      RECT 21.087 0.000 21.105 0.270 ;
    END
  END rw0_rd_out[52]
  PIN rw0_rd_out[53]
    DIRECTION OUTPUT ;
    USE SIGNAL ;
    SHAPE ABUTMENT ;
    PORT
      LAYER M2 ;
      RECT 21.267 0.000 21.285 0.270 ;
    END
  END rw0_rd_out[53]
  PIN rw0_rd_out[54]
    DIRECTION OUTPUT ;
    USE SIGNAL ;
    SHAPE ABUTMENT ;
    PORT
      LAYER M2 ;
      RECT 21.447 0.000 21.465 0.270 ;
    END
  END rw0_rd_out[54]
  PIN rw0_rd_out[55]
    DIRECTION OUTPUT ;
    USE SIGNAL ;
    SHAPE ABUTMENT ;
    PORT
      LAYER M2 ;
      RECT 21.627 0.000 21.645 0.270 ;
    END
  END rw0_rd_out[55]
  PIN rw0_rd_out[56]
    DIRECTION OUTPUT ;
    USE SIGNAL ;
    SHAPE ABUTMENT ;
    PORT
      LAYER M2 ;
      RECT 21.807 0.000 21.825 0.270 ;
    END
  END rw0_rd_out[56]
  PIN rw0_rd_out[57]
    DIRECTION OUTPUT ;
    USE SIGNAL ;
    SHAPE ABUTMENT ;
    PORT
      LAYER M2 ;
      RECT 21.987 0.000 22.005 0.270 ;
    END
  END rw0_rd_out[57]
  PIN rw0_rd_out[58]
    DIRECTION OUTPUT ;
    USE SIGNAL ;
    SHAPE ABUTMENT ;
    PORT
      LAYER M2 ;
      RECT 22.167 0.000 22.185 0.270 ;
    END
  END rw0_rd_out[58]
  PIN rw0_rd_out[59]
    DIRECTION OUTPUT ;
    USE SIGNAL ;
    SHAPE ABUTMENT ;
    PORT
      LAYER M2 ;
      RECT 22.347 0.000 22.365 0.270 ;
    END
  END rw0_rd_out[59]
  PIN rw0_rd_out[60]
    DIRECTION OUTPUT ;
    USE SIGNAL ;
    SHAPE ABUTMENT ;
    PORT
      LAYER M2 ;
      RECT 22.527 0.000 22.545 0.270 ;
    END
  END rw0_rd_out[60]
  PIN rw0_rd_out[61]
    DIRECTION OUTPUT ;
    USE SIGNAL ;
    SHAPE ABUTMENT ;
    PORT
      LAYER M2 ;
      RECT 22.707 0.000 22.725 0.270 ;
    END
  END rw0_rd_out[61]
  PIN rw0_rd_out[62]
    DIRECTION OUTPUT ;
    USE SIGNAL ;
    SHAPE ABUTMENT ;
    PORT
      LAYER M2 ;
      RECT 22.887 0.000 22.905 0.270 ;
    END
  END rw0_rd_out[62]
  PIN rw0_rd_out[63]
    DIRECTION OUTPUT ;
    USE SIGNAL ;
    SHAPE ABUTMENT ;
    PORT
      LAYER M2 ;
      RECT 23.067 0.000 23.085 0.270 ;
    END
  END rw0_rd_out[63]
  PIN rw0_rd_out[64]
    DIRECTION OUTPUT ;
    USE SIGNAL ;
    SHAPE ABUTMENT ;
    PORT
      LAYER M2 ;
      RECT 2.799 64.800 2.817 65.070 ;
    END
  END rw0_rd_out[64]
  PIN rw0_rd_out[65]
    DIRECTION OUTPUT ;
    USE SIGNAL ;
    SHAPE ABUTMENT ;
    PORT
      LAYER M2 ;
      RECT 3.123 64.800 3.141 65.070 ;
    END
  END rw0_rd_out[65]
  PIN rw0_rd_out[66]
    DIRECTION OUTPUT ;
    USE SIGNAL ;
    SHAPE ABUTMENT ;
    PORT
      LAYER M2 ;
      RECT 3.447 64.800 3.465 65.070 ;
    END
  END rw0_rd_out[66]
  PIN rw0_rd_out[67]
    DIRECTION OUTPUT ;
    USE SIGNAL ;
    SHAPE ABUTMENT ;
    PORT
      LAYER M2 ;
      RECT 3.771 64.800 3.789 65.070 ;
    END
  END rw0_rd_out[67]
  PIN rw0_rd_out[68]
    DIRECTION OUTPUT ;
    USE SIGNAL ;
    SHAPE ABUTMENT ;
    PORT
      LAYER M2 ;
      RECT 4.095 64.800 4.113 65.070 ;
    END
  END rw0_rd_out[68]
  PIN rw0_rd_out[69]
    DIRECTION OUTPUT ;
    USE SIGNAL ;
    SHAPE ABUTMENT ;
    PORT
      LAYER M2 ;
      RECT 4.419 64.800 4.437 65.070 ;
    END
  END rw0_rd_out[69]
  PIN rw0_rd_out[70]
    DIRECTION OUTPUT ;
    USE SIGNAL ;
    SHAPE ABUTMENT ;
    PORT
      LAYER M2 ;
      RECT 4.743 64.800 4.761 65.070 ;
    END
  END rw0_rd_out[70]
  PIN rw0_rd_out[71]
    DIRECTION OUTPUT ;
    USE SIGNAL ;
    SHAPE ABUTMENT ;
    PORT
      LAYER M2 ;
      RECT 5.067 64.800 5.085 65.070 ;
    END
  END rw0_rd_out[71]
  PIN rw0_rd_out[72]
    DIRECTION OUTPUT ;
    USE SIGNAL ;
    SHAPE ABUTMENT ;
    PORT
      LAYER M2 ;
      RECT 5.391 64.800 5.409 65.070 ;
    END
  END rw0_rd_out[72]
  PIN rw0_rd_out[73]
    DIRECTION OUTPUT ;
    USE SIGNAL ;
    SHAPE ABUTMENT ;
    PORT
      LAYER M2 ;
      RECT 5.715 64.800 5.733 65.070 ;
    END
  END rw0_rd_out[73]
  PIN rw0_rd_out[74]
    DIRECTION OUTPUT ;
    USE SIGNAL ;
    SHAPE ABUTMENT ;
    PORT
      LAYER M2 ;
      RECT 6.039 64.800 6.057 65.070 ;
    END
  END rw0_rd_out[74]
  PIN rw0_rd_out[75]
    DIRECTION OUTPUT ;
    USE SIGNAL ;
    SHAPE ABUTMENT ;
    PORT
      LAYER M2 ;
      RECT 6.363 64.800 6.381 65.070 ;
    END
  END rw0_rd_out[75]
  PIN rw0_rd_out[76]
    DIRECTION OUTPUT ;
    USE SIGNAL ;
    SHAPE ABUTMENT ;
    PORT
      LAYER M2 ;
      RECT 6.687 64.800 6.705 65.070 ;
    END
  END rw0_rd_out[76]
  PIN rw0_rd_out[77]
    DIRECTION OUTPUT ;
    USE SIGNAL ;
    SHAPE ABUTMENT ;
    PORT
      LAYER M2 ;
      RECT 7.011 64.800 7.029 65.070 ;
    END
  END rw0_rd_out[77]
  PIN rw0_rd_out[78]
    DIRECTION OUTPUT ;
    USE SIGNAL ;
    SHAPE ABUTMENT ;
    PORT
      LAYER M2 ;
      RECT 7.335 64.800 7.353 65.070 ;
    END
  END rw0_rd_out[78]
  PIN rw0_rd_out[79]
    DIRECTION OUTPUT ;
    USE SIGNAL ;
    SHAPE ABUTMENT ;
    PORT
      LAYER M2 ;
      RECT 7.659 64.800 7.677 65.070 ;
    END
  END rw0_rd_out[79]
  PIN rw0_rd_out[80]
    DIRECTION OUTPUT ;
    USE SIGNAL ;
    SHAPE ABUTMENT ;
    PORT
      LAYER M2 ;
      RECT 7.983 64.800 8.001 65.070 ;
    END
  END rw0_rd_out[80]
  PIN rw0_rd_out[81]
    DIRECTION OUTPUT ;
    USE SIGNAL ;
    SHAPE ABUTMENT ;
    PORT
      LAYER M2 ;
      RECT 8.307 64.800 8.325 65.070 ;
    END
  END rw0_rd_out[81]
  PIN rw0_rd_out[82]
    DIRECTION OUTPUT ;
    USE SIGNAL ;
    SHAPE ABUTMENT ;
    PORT
      LAYER M2 ;
      RECT 8.631 64.800 8.649 65.070 ;
    END
  END rw0_rd_out[82]
  PIN rw0_rd_out[83]
    DIRECTION OUTPUT ;
    USE SIGNAL ;
    SHAPE ABUTMENT ;
    PORT
      LAYER M2 ;
      RECT 8.955 64.800 8.973 65.070 ;
    END
  END rw0_rd_out[83]
  PIN rw0_rd_out[84]
    DIRECTION OUTPUT ;
    USE SIGNAL ;
    SHAPE ABUTMENT ;
    PORT
      LAYER M2 ;
      RECT 9.279 64.800 9.297 65.070 ;
    END
  END rw0_rd_out[84]
  PIN rw0_rd_out[85]
    DIRECTION OUTPUT ;
    USE SIGNAL ;
    SHAPE ABUTMENT ;
    PORT
      LAYER M2 ;
      RECT 9.603 64.800 9.621 65.070 ;
    END
  END rw0_rd_out[85]
  PIN rw0_rd_out[86]
    DIRECTION OUTPUT ;
    USE SIGNAL ;
    SHAPE ABUTMENT ;
    PORT
      LAYER M2 ;
      RECT 9.927 64.800 9.945 65.070 ;
    END
  END rw0_rd_out[86]
  PIN rw0_rd_out[87]
    DIRECTION OUTPUT ;
    USE SIGNAL ;
    SHAPE ABUTMENT ;
    PORT
      LAYER M2 ;
      RECT 10.251 64.800 10.269 65.070 ;
    END
  END rw0_rd_out[87]
  PIN rw0_rd_out[88]
    DIRECTION OUTPUT ;
    USE SIGNAL ;
    SHAPE ABUTMENT ;
    PORT
      LAYER M2 ;
      RECT 10.575 64.800 10.593 65.070 ;
    END
  END rw0_rd_out[88]
  PIN rw0_rd_out[89]
    DIRECTION OUTPUT ;
    USE SIGNAL ;
    SHAPE ABUTMENT ;
    PORT
      LAYER M2 ;
      RECT 10.899 64.800 10.917 65.070 ;
    END
  END rw0_rd_out[89]
  PIN rw0_rd_out[90]
    DIRECTION OUTPUT ;
    USE SIGNAL ;
    SHAPE ABUTMENT ;
    PORT
      LAYER M2 ;
      RECT 11.223 64.800 11.241 65.070 ;
    END
  END rw0_rd_out[90]
  PIN rw0_rd_out[91]
    DIRECTION OUTPUT ;
    USE SIGNAL ;
    SHAPE ABUTMENT ;
    PORT
      LAYER M2 ;
      RECT 11.547 64.800 11.565 65.070 ;
    END
  END rw0_rd_out[91]
  PIN rw0_rd_out[92]
    DIRECTION OUTPUT ;
    USE SIGNAL ;
    SHAPE ABUTMENT ;
    PORT
      LAYER M2 ;
      RECT 11.871 64.800 11.889 65.070 ;
    END
  END rw0_rd_out[92]
  PIN rw0_rd_out[93]
    DIRECTION OUTPUT ;
    USE SIGNAL ;
    SHAPE ABUTMENT ;
    PORT
      LAYER M2 ;
      RECT 12.195 64.800 12.213 65.070 ;
    END
  END rw0_rd_out[93]
  PIN rw0_rd_out[94]
    DIRECTION OUTPUT ;
    USE SIGNAL ;
    SHAPE ABUTMENT ;
    PORT
      LAYER M2 ;
      RECT 12.519 64.800 12.537 65.070 ;
    END
  END rw0_rd_out[94]
  PIN rw0_rd_out[95]
    DIRECTION OUTPUT ;
    USE SIGNAL ;
    SHAPE ABUTMENT ;
    PORT
      LAYER M2 ;
      RECT 12.843 64.800 12.861 65.070 ;
    END
  END rw0_rd_out[95]
  PIN rw0_rd_out[96]
    DIRECTION OUTPUT ;
    USE SIGNAL ;
    SHAPE ABUTMENT ;
    PORT
      LAYER M2 ;
      RECT 13.167 64.800 13.185 65.070 ;
    END
  END rw0_rd_out[96]
  PIN rw0_rd_out[97]
    DIRECTION OUTPUT ;
    USE SIGNAL ;
    SHAPE ABUTMENT ;
    PORT
      LAYER M2 ;
      RECT 13.491 64.800 13.509 65.070 ;
    END
  END rw0_rd_out[97]
  PIN rw0_rd_out[98]
    DIRECTION OUTPUT ;
    USE SIGNAL ;
    SHAPE ABUTMENT ;
    PORT
      LAYER M2 ;
      RECT 13.815 64.800 13.833 65.070 ;
    END
  END rw0_rd_out[98]
  PIN rw0_rd_out[99]
    DIRECTION OUTPUT ;
    USE SIGNAL ;
    SHAPE ABUTMENT ;
    PORT
      LAYER M2 ;
      RECT 14.139 64.800 14.157 65.070 ;
    END
  END rw0_rd_out[99]
  PIN rw0_rd_out[100]
    DIRECTION OUTPUT ;
    USE SIGNAL ;
    SHAPE ABUTMENT ;
    PORT
      LAYER M2 ;
      RECT 14.463 64.800 14.481 65.070 ;
    END
  END rw0_rd_out[100]
  PIN rw0_rd_out[101]
    DIRECTION OUTPUT ;
    USE SIGNAL ;
    SHAPE ABUTMENT ;
    PORT
      LAYER M2 ;
      RECT 14.787 64.800 14.805 65.070 ;
    END
  END rw0_rd_out[101]
  PIN rw0_rd_out[102]
    DIRECTION OUTPUT ;
    USE SIGNAL ;
    SHAPE ABUTMENT ;
    PORT
      LAYER M2 ;
      RECT 15.111 64.800 15.129 65.070 ;
    END
  END rw0_rd_out[102]
  PIN rw0_rd_out[103]
    DIRECTION OUTPUT ;
    USE SIGNAL ;
    SHAPE ABUTMENT ;
    PORT
      LAYER M2 ;
      RECT 15.435 64.800 15.453 65.070 ;
    END
  END rw0_rd_out[103]
  PIN rw0_rd_out[104]
    DIRECTION OUTPUT ;
    USE SIGNAL ;
    SHAPE ABUTMENT ;
    PORT
      LAYER M2 ;
      RECT 15.759 64.800 15.777 65.070 ;
    END
  END rw0_rd_out[104]
  PIN rw0_rd_out[105]
    DIRECTION OUTPUT ;
    USE SIGNAL ;
    SHAPE ABUTMENT ;
    PORT
      LAYER M2 ;
      RECT 16.083 64.800 16.101 65.070 ;
    END
  END rw0_rd_out[105]
  PIN rw0_rd_out[106]
    DIRECTION OUTPUT ;
    USE SIGNAL ;
    SHAPE ABUTMENT ;
    PORT
      LAYER M2 ;
      RECT 16.407 64.800 16.425 65.070 ;
    END
  END rw0_rd_out[106]
  PIN rw0_rd_out[107]
    DIRECTION OUTPUT ;
    USE SIGNAL ;
    SHAPE ABUTMENT ;
    PORT
      LAYER M2 ;
      RECT 16.731 64.800 16.749 65.070 ;
    END
  END rw0_rd_out[107]
  PIN rw0_rd_out[108]
    DIRECTION OUTPUT ;
    USE SIGNAL ;
    SHAPE ABUTMENT ;
    PORT
      LAYER M2 ;
      RECT 17.055 64.800 17.073 65.070 ;
    END
  END rw0_rd_out[108]
  PIN rw0_rd_out[109]
    DIRECTION OUTPUT ;
    USE SIGNAL ;
    SHAPE ABUTMENT ;
    PORT
      LAYER M2 ;
      RECT 17.379 64.800 17.397 65.070 ;
    END
  END rw0_rd_out[109]
  PIN rw0_rd_out[110]
    DIRECTION OUTPUT ;
    USE SIGNAL ;
    SHAPE ABUTMENT ;
    PORT
      LAYER M2 ;
      RECT 17.703 64.800 17.721 65.070 ;
    END
  END rw0_rd_out[110]
  PIN rw0_rd_out[111]
    DIRECTION OUTPUT ;
    USE SIGNAL ;
    SHAPE ABUTMENT ;
    PORT
      LAYER M2 ;
      RECT 18.027 64.800 18.045 65.070 ;
    END
  END rw0_rd_out[111]
  PIN rw0_rd_out[112]
    DIRECTION OUTPUT ;
    USE SIGNAL ;
    SHAPE ABUTMENT ;
    PORT
      LAYER M2 ;
      RECT 18.351 64.800 18.369 65.070 ;
    END
  END rw0_rd_out[112]
  PIN rw0_rd_out[113]
    DIRECTION OUTPUT ;
    USE SIGNAL ;
    SHAPE ABUTMENT ;
    PORT
      LAYER M2 ;
      RECT 18.675 64.800 18.693 65.070 ;
    END
  END rw0_rd_out[113]
  PIN rw0_rd_out[114]
    DIRECTION OUTPUT ;
    USE SIGNAL ;
    SHAPE ABUTMENT ;
    PORT
      LAYER M2 ;
      RECT 18.999 64.800 19.017 65.070 ;
    END
  END rw0_rd_out[114]
  PIN rw0_rd_out[115]
    DIRECTION OUTPUT ;
    USE SIGNAL ;
    SHAPE ABUTMENT ;
    PORT
      LAYER M2 ;
      RECT 19.323 64.800 19.341 65.070 ;
    END
  END rw0_rd_out[115]
  PIN rw0_rd_out[116]
    DIRECTION OUTPUT ;
    USE SIGNAL ;
    SHAPE ABUTMENT ;
    PORT
      LAYER M2 ;
      RECT 19.647 64.800 19.665 65.070 ;
    END
  END rw0_rd_out[116]
  PIN rw0_rd_out[117]
    DIRECTION OUTPUT ;
    USE SIGNAL ;
    SHAPE ABUTMENT ;
    PORT
      LAYER M2 ;
      RECT 19.971 64.800 19.989 65.070 ;
    END
  END rw0_rd_out[117]
  PIN rw0_rd_out[118]
    DIRECTION OUTPUT ;
    USE SIGNAL ;
    SHAPE ABUTMENT ;
    PORT
      LAYER M2 ;
      RECT 20.295 64.800 20.313 65.070 ;
    END
  END rw0_rd_out[118]
  PIN rw0_rd_out[119]
    DIRECTION OUTPUT ;
    USE SIGNAL ;
    SHAPE ABUTMENT ;
    PORT
      LAYER M2 ;
      RECT 20.619 64.800 20.637 65.070 ;
    END
  END rw0_rd_out[119]
  PIN rw0_rd_out[120]
    DIRECTION OUTPUT ;
    USE SIGNAL ;
    SHAPE ABUTMENT ;
    PORT
      LAYER M2 ;
      RECT 20.943 64.800 20.961 65.070 ;
    END
  END rw0_rd_out[120]
  PIN rw0_rd_out[121]
    DIRECTION OUTPUT ;
    USE SIGNAL ;
    SHAPE ABUTMENT ;
    PORT
      LAYER M2 ;
      RECT 21.267 64.800 21.285 65.070 ;
    END
  END rw0_rd_out[121]
  PIN rw0_rd_out[122]
    DIRECTION OUTPUT ;
    USE SIGNAL ;
    SHAPE ABUTMENT ;
    PORT
      LAYER M2 ;
      RECT 21.591 64.800 21.609 65.070 ;
    END
  END rw0_rd_out[122]
  PIN rw0_rd_out[123]
    DIRECTION OUTPUT ;
    USE SIGNAL ;
    SHAPE ABUTMENT ;
    PORT
      LAYER M2 ;
      RECT 21.915 64.800 21.933 65.070 ;
    END
  END rw0_rd_out[123]
  PIN rw0_rd_out[124]
    DIRECTION OUTPUT ;
    USE SIGNAL ;
    SHAPE ABUTMENT ;
    PORT
      LAYER M2 ;
      RECT 22.239 64.800 22.257 65.070 ;
    END
  END rw0_rd_out[124]
  PIN rw0_rd_out[125]
    DIRECTION OUTPUT ;
    USE SIGNAL ;
    SHAPE ABUTMENT ;
    PORT
      LAYER M2 ;
      RECT 22.563 64.800 22.581 65.070 ;
    END
  END rw0_rd_out[125]
  PIN rw0_rd_out[126]
    DIRECTION OUTPUT ;
    USE SIGNAL ;
    SHAPE ABUTMENT ;
    PORT
      LAYER M2 ;
      RECT 22.887 64.800 22.905 65.070 ;
    END
  END rw0_rd_out[126]
  PIN rw0_rd_out[127]
    DIRECTION OUTPUT ;
    USE SIGNAL ;
    SHAPE ABUTMENT ;
    PORT
      LAYER M2 ;
      RECT 23.211 64.800 23.229 65.070 ;
    END
  END rw0_rd_out[127]
  PIN rw0_addr_in[0]
    DIRECTION INPUT ;
    USE SIGNAL ;
    SHAPE ABUTMENT ;
    PORT
      LAYER M3 ;
      RECT 0.000 55.572 0.072 55.596 ;
    END
  END rw0_addr_in[0]
  PIN rw0_addr_in[1]
    DIRECTION INPUT ;
    USE SIGNAL ;
    SHAPE ABUTMENT ;
    PORT
      LAYER M3 ;
      RECT 0.000 57.108 0.072 57.132 ;
    END
  END rw0_addr_in[1]
  PIN rw0_addr_in[2]
    DIRECTION INPUT ;
    USE SIGNAL ;
    SHAPE ABUTMENT ;
    PORT
      LAYER M3 ;
      RECT 0.000 58.644 0.072 58.668 ;
    END
  END rw0_addr_in[2]
  PIN rw0_addr_in[3]
    DIRECTION INPUT ;
    USE SIGNAL ;
    SHAPE ABUTMENT ;
    PORT
      LAYER M3 ;
      RECT 0.000 60.180 0.072 60.204 ;
    END
  END rw0_addr_in[3]
  PIN rw0_addr_in[4]
    DIRECTION INPUT ;
    USE SIGNAL ;
    SHAPE ABUTMENT ;
    PORT
      LAYER M3 ;
      RECT 0.000 61.716 0.072 61.740 ;
    END
  END rw0_addr_in[4]
  PIN rw0_addr_in[5]
    DIRECTION INPUT ;
    USE SIGNAL ;
    SHAPE ABUTMENT ;
    PORT
      LAYER M3 ;
      RECT 25.956 55.572 26.028 55.596 ;
    END
  END rw0_addr_in[5]
  PIN rw0_addr_in[6]
    DIRECTION INPUT ;
    USE SIGNAL ;
    SHAPE ABUTMENT ;
    PORT
      LAYER M3 ;
      RECT 25.956 57.108 26.028 57.132 ;
    END
  END rw0_addr_in[6]
  PIN rw0_addr_in[7]
    DIRECTION INPUT ;
    USE SIGNAL ;
    SHAPE ABUTMENT ;
    PORT
      LAYER M3 ;
      RECT 25.956 58.644 26.028 58.668 ;
    END
  END rw0_addr_in[7]
  PIN rw0_addr_in[8]
    DIRECTION INPUT ;
    USE SIGNAL ;
    SHAPE ABUTMENT ;
    PORT
      LAYER M3 ;
      RECT 25.956 60.180 26.028 60.204 ;
    END
  END rw0_addr_in[8]
  PIN rw0_we_in
    DIRECTION INPUT ;
    USE SIGNAL ;
    SHAPE ABUTMENT ;
    PORT
      LAYER M2 ;
      RECT 23.535 64.800 23.553 65.070 ;
    END
  END rw0_we_in
  PIN rw0_ce_in
    DIRECTION INPUT ;
    USE SIGNAL ;
    SHAPE ABUTMENT ;
    PORT
      LAYER M2 ;
      RECT 23.859 64.800 23.877 65.070 ;
    END
  END rw0_ce_in
  PIN rw0_clk
    DIRECTION INPUT ;
    USE SIGNAL ;
    SHAPE ABUTMENT ;
    PORT
      LAYER M2 ;
      RECT 24.183 64.800 24.201 65.070 ;
    END
  END rw0_clk
  PIN VSS
    DIRECTION INOUT ;
    USE GROUND ;
    PORT
      LAYER M4 ;
      RECT 0.216 0.228 25.812 0.348 ;
      RECT 0.216 0.996 25.812 1.116 ;
      RECT 0.216 1.764 25.812 1.884 ;
      RECT 0.216 2.532 25.812 2.652 ;
      RECT 0.216 3.300 25.812 3.420 ;
      RECT 0.216 4.068 25.812 4.188 ;
      RECT 0.216 4.836 25.812 4.956 ;
      RECT 0.216 5.604 25.812 5.724 ;
      RECT 0.216 6.372 25.812 6.492 ;
      RECT 0.216 7.140 25.812 7.260 ;
      RECT 0.216 7.908 25.812 8.028 ;
      RECT 0.216 8.676 25.812 8.796 ;
      RECT 0.216 9.444 25.812 9.564 ;
      RECT 0.216 10.212 25.812 10.332 ;
      RECT 0.216 10.980 25.812 11.100 ;
      RECT 0.216 11.748 25.812 11.868 ;
      RECT 0.216 12.516 25.812 12.636 ;
      RECT 0.216 13.284 25.812 13.404 ;
      RECT 0.216 14.052 25.812 14.172 ;
      RECT 0.216 14.820 25.812 14.940 ;
      RECT 0.216 15.588 25.812 15.708 ;
      RECT 0.216 16.356 25.812 16.476 ;
      RECT 0.216 17.124 25.812 17.244 ;
      RECT 0.216 17.892 25.812 18.012 ;
      RECT 0.216 18.660 25.812 18.780 ;
      RECT 0.216 19.428 25.812 19.548 ;
      RECT 0.216 20.196 25.812 20.316 ;
      RECT 0.216 20.964 25.812 21.084 ;
      RECT 0.216 21.732 25.812 21.852 ;
      RECT 0.216 22.500 25.812 22.620 ;
      RECT 0.216 23.268 25.812 23.388 ;
      RECT 0.216 24.036 25.812 24.156 ;
      RECT 0.216 24.804 25.812 24.924 ;
      RECT 0.216 25.572 25.812 25.692 ;
      RECT 0.216 26.340 25.812 26.460 ;
      RECT 0.216 27.108 25.812 27.228 ;
      RECT 0.216 27.876 25.812 27.996 ;
      RECT 0.216 28.644 25.812 28.764 ;
      RECT 0.216 29.412 25.812 29.532 ;
      RECT 0.216 30.180 25.812 30.300 ;
      RECT 0.216 30.948 25.812 31.068 ;
      RECT 0.216 31.716 25.812 31.836 ;
      RECT 0.216 32.484 25.812 32.604 ;
      RECT 0.216 33.252 25.812 33.372 ;
      RECT 0.216 34.020 25.812 34.140 ;
      RECT 0.216 34.788 25.812 34.908 ;
      RECT 0.216 35.556 25.812 35.676 ;
      RECT 0.216 36.324 25.812 36.444 ;
      RECT 0.216 37.092 25.812 37.212 ;
      RECT 0.216 37.860 25.812 37.980 ;
      RECT 0.216 38.628 25.812 38.748 ;
      RECT 0.216 39.396 25.812 39.516 ;
      RECT 0.216 40.164 25.812 40.284 ;
      RECT 0.216 40.932 25.812 41.052 ;
      RECT 0.216 41.700 25.812 41.820 ;
      RECT 0.216 42.468 25.812 42.588 ;
      RECT 0.216 43.236 25.812 43.356 ;
      RECT 0.216 44.004 25.812 44.124 ;
      RECT 0.216 44.772 25.812 44.892 ;
      RECT 0.216 45.540 25.812 45.660 ;
      RECT 0.216 46.308 25.812 46.428 ;
      RECT 0.216 47.076 25.812 47.196 ;
      RECT 0.216 47.844 25.812 47.964 ;
      RECT 0.216 48.612 25.812 48.732 ;
      RECT 0.216 49.380 25.812 49.500 ;
      RECT 0.216 50.148 25.812 50.268 ;
      RECT 0.216 50.916 25.812 51.036 ;
      RECT 0.216 51.684 25.812 51.804 ;
      RECT 0.216 52.452 25.812 52.572 ;
      RECT 0.216 53.220 25.812 53.340 ;
      RECT 0.216 53.988 25.812 54.108 ;
      RECT 0.216 54.756 25.812 54.876 ;
      RECT 0.216 55.524 25.812 55.644 ;
      RECT 0.216 56.292 25.812 56.412 ;
      RECT 0.216 57.060 25.812 57.180 ;
      RECT 0.216 57.828 25.812 57.948 ;
      RECT 0.216 58.596 25.812 58.716 ;
      RECT 0.216 59.364 25.812 59.484 ;
      RECT 0.216 60.132 25.812 60.252 ;
      RECT 0.216 60.900 25.812 61.020 ;
      RECT 0.216 61.668 25.812 61.788 ;
      RECT 0.216 62.436 25.812 62.556 ;
      RECT 0.216 63.204 25.812 63.324 ;
      RECT 0.216 63.972 25.812 64.092 ;
      RECT 0.216 64.740 25.812 64.860 ;
    END
  END VSS
  PIN VDD
    DIRECTION INOUT ;
    USE POWER ;
    PORT
      LAYER M4 ;
      RECT 0.216 0.612 25.812 0.732 ;
      RECT 0.216 1.380 25.812 1.500 ;
      RECT 0.216 2.148 25.812 2.268 ;
      RECT 0.216 2.916 25.812 3.036 ;
      RECT 0.216 3.684 25.812 3.804 ;
      RECT 0.216 4.452 25.812 4.572 ;
      RECT 0.216 5.220 25.812 5.340 ;
      RECT 0.216 5.988 25.812 6.108 ;
      RECT 0.216 6.756 25.812 6.876 ;
      RECT 0.216 7.524 25.812 7.644 ;
      RECT 0.216 8.292 25.812 8.412 ;
      RECT 0.216 9.060 25.812 9.180 ;
      RECT 0.216 9.828 25.812 9.948 ;
      RECT 0.216 10.596 25.812 10.716 ;
      RECT 0.216 11.364 25.812 11.484 ;
      RECT 0.216 12.132 25.812 12.252 ;
      RECT 0.216 12.900 25.812 13.020 ;
      RECT 0.216 13.668 25.812 13.788 ;
      RECT 0.216 14.436 25.812 14.556 ;
      RECT 0.216 15.204 25.812 15.324 ;
      RECT 0.216 15.972 25.812 16.092 ;
      RECT 0.216 16.740 25.812 16.860 ;
      RECT 0.216 17.508 25.812 17.628 ;
      RECT 0.216 18.276 25.812 18.396 ;
      RECT 0.216 19.044 25.812 19.164 ;
      RECT 0.216 19.812 25.812 19.932 ;
      RECT 0.216 20.580 25.812 20.700 ;
      RECT 0.216 21.348 25.812 21.468 ;
      RECT 0.216 22.116 25.812 22.236 ;
      RECT 0.216 22.884 25.812 23.004 ;
      RECT 0.216 23.652 25.812 23.772 ;
      RECT 0.216 24.420 25.812 24.540 ;
      RECT 0.216 25.188 25.812 25.308 ;
      RECT 0.216 25.956 25.812 26.076 ;
      RECT 0.216 26.724 25.812 26.844 ;
      RECT 0.216 27.492 25.812 27.612 ;
      RECT 0.216 28.260 25.812 28.380 ;
      RECT 0.216 29.028 25.812 29.148 ;
      RECT 0.216 29.796 25.812 29.916 ;
      RECT 0.216 30.564 25.812 30.684 ;
      RECT 0.216 31.332 25.812 31.452 ;
      RECT 0.216 32.100 25.812 32.220 ;
      RECT 0.216 32.868 25.812 32.988 ;
      RECT 0.216 33.636 25.812 33.756 ;
      RECT 0.216 34.404 25.812 34.524 ;
      RECT 0.216 35.172 25.812 35.292 ;
      RECT 0.216 35.940 25.812 36.060 ;
      RECT 0.216 36.708 25.812 36.828 ;
      RECT 0.216 37.476 25.812 37.596 ;
      RECT 0.216 38.244 25.812 38.364 ;
      RECT 0.216 39.012 25.812 39.132 ;
      RECT 0.216 39.780 25.812 39.900 ;
      RECT 0.216 40.548 25.812 40.668 ;
      RECT 0.216 41.316 25.812 41.436 ;
      RECT 0.216 42.084 25.812 42.204 ;
      RECT 0.216 42.852 25.812 42.972 ;
      RECT 0.216 43.620 25.812 43.740 ;
      RECT 0.216 44.388 25.812 44.508 ;
      RECT 0.216 45.156 25.812 45.276 ;
      RECT 0.216 45.924 25.812 46.044 ;
      RECT 0.216 46.692 25.812 46.812 ;
      RECT 0.216 47.460 25.812 47.580 ;
      RECT 0.216 48.228 25.812 48.348 ;
      RECT 0.216 48.996 25.812 49.116 ;
      RECT 0.216 49.764 25.812 49.884 ;
      RECT 0.216 50.532 25.812 50.652 ;
      RECT 0.216 51.300 25.812 51.420 ;
      RECT 0.216 52.068 25.812 52.188 ;
      RECT 0.216 52.836 25.812 52.956 ;
      RECT 0.216 53.604 25.812 53.724 ;
      RECT 0.216 54.372 25.812 54.492 ;
      RECT 0.216 55.140 25.812 55.260 ;
      RECT 0.216 55.908 25.812 56.028 ;
      RECT 0.216 56.676 25.812 56.796 ;
      RECT 0.216 57.444 25.812 57.564 ;
      RECT 0.216 58.212 25.812 58.332 ;
      RECT 0.216 58.980 25.812 59.100 ;
      RECT 0.216 59.748 25.812 59.868 ;
      RECT 0.216 60.516 25.812 60.636 ;
      RECT 0.216 61.284 25.812 61.404 ;
      RECT 0.216 62.052 25.812 62.172 ;
      RECT 0.216 62.820 25.812 62.940 ;
      RECT 0.216 63.588 25.812 63.708 ;
      RECT 0.216 64.356 25.812 64.476 ;
    END
  END VDD
  OBS
    LAYER M1 ;
    RECT 0 0 26.028 65.070 ;
    LAYER M2 ;
    RECT 0 0 26.028 65.070 ;
    LAYER M3 ;
    RECT 0 0 26.028 65.070 ;
    LAYER M4 ;
    RECT 0 0 26.028 65.070 ;
  END
END ht_asap7_coralnpu_512x128

END LIBRARY
